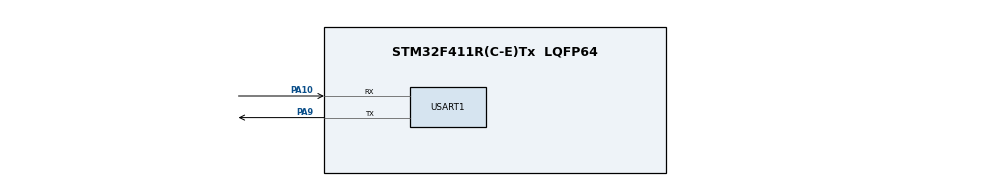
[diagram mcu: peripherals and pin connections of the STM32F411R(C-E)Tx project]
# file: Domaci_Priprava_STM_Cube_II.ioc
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Mcu.Family=STM32F4
Mcu.Name=STM32F411R(C-E)Tx
Mcu.Package=LQFP64
NVIC.PriorityGroup=NVIC_PRIORITYGROUP_4
PA10.Mode=Asynchronous
PA10.Signal=USART1_RX
PA9.Mode=Asynchronous
PA9.Signal=USART1_TX
PH0\ -\ OSC_IN.Mode=HSE-External-Clock-Source
PH0\ -\ OSC_IN.Signal=RCC_OSC_IN
PH1\ -\ OSC_OUT.Mode=HSE-External-Clock-Source
PH1\ -\ OSC_OUT.Signal=RCC_OSC_OUT
ProjectManager.HeapSize=0x200
ProjectManager.StackSize=0x400
ProjectManager.TargetToolchain=TrueSTUDIO
RCC.48MHZClocksFreq_Value=50000000
RCC.AHBFreq_Value=16000000
RCC.APB1CLKDivider=RCC_HCLK_DIV2
RCC.APB1Freq_Value=8000000
RCC.APB1TimFreq_Value=16000000
RCC.APB2Freq_Value=16000000
RCC.APB2TimFreq_Value=16000000
RCC.CortexFreq_Value=16000000
RCC.HCLKFreq_Value=16000000
RCC.HSE_VALUE=8000000
RCC.HSI_VALUE=16000000
RCC.LSE_VALUE=32768
RCC.PLLM=8
RCC.PLLN=100
RCC.SYSCLKFreq_VALUE=16000000
RCC.VCOOutputFreq_Value=200000000
USART1.VirtualMode=VM_ASYNC
board=custom

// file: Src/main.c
/* USER CODE BEGIN Header */
/**
  ******************************************************************************
  * @file           : main.c
  * @brief          : Main program body
  ******************************************************************************
  * @attention
  *
  * <h2><center>&copy; Copyright (c) 2019 STMicroelectronics.
  * All rights reserved.</center></h2>
  *
  * This software component is licensed by ST under BSD 3-Clause license,
  * the "License"; You may not use this file except in compliance with the
  * License. You may obtain a copy of the License at:
  *                        opensource.org/licenses/BSD-3-Clause
  *
  ******************************************************************************
  */
/* USER CODE END Header */

#include "main.h"

UART_HandleTypeDef huart1;

void SystemClock_Config(void);
static void MX_GPIO_Init(void);
static void MX_USART1_UART_Init(void);

int main(void)
{

  /* MCU Configuration--------------------------------------------------------*/

  /* Reset of all peripherals, Initializes the Flash interface and the Systick. */
  HAL_Init();

  /* Configure the system clock */
  SystemClock_Config();

  /* Initialize all configured peripherals */
  MX_GPIO_Init();
  MX_USART1_UART_Init();

  /* Infinite loop */
  while (1)
  {

  }
}

void SystemClock_Config(void)
{
  RCC_OscInitTypeDef RCC_OscInitStruct = {0};
  RCC_ClkInitTypeDef RCC_ClkInitStruct = {0};

  /** Configure the main internal regulator output voltage
  */
  __HAL_RCC_PWR_CLK_ENABLE();
  __HAL_PWR_VOLTAGESCALING_CONFIG(PWR_REGULATOR_VOLTAGE_SCALE1);
  /** Initializes the CPU, AHB and APB busses clocks
  */
  RCC_OscInitStruct.OscillatorType = RCC_OSCILLATORTYPE_HSE;
  RCC_OscInitStruct.HSEState = RCC_HSE_BYPASS;
  RCC_OscInitStruct.PLL.PLLState = RCC_PLL_ON;
  RCC_OscInitStruct.PLL.PLLSource = RCC_PLLSOURCE_HSE;
  RCC_OscInitStruct.PLL.PLLM = 4;
  RCC_OscInitStruct.PLL.PLLN = 100;
  RCC_OscInitStruct.PLL.PLLP = RCC_PLLP_DIV2;
  RCC_OscInitStruct.PLL.PLLQ = 4;
  if (HAL_RCC_OscConfig(&RCC_OscInitStruct) != HAL_OK)
  {
    Error_Handler();
  }
  /** Initializes the CPU, AHB and APB busses clocks
  */
  RCC_ClkInitStruct.ClockType = RCC_CLOCKTYPE_HCLK|RCC_CLOCKTYPE_SYSCLK
                              |RCC_CLOCKTYPE_PCLK1|RCC_CLOCKTYPE_PCLK2;
  RCC_ClkInitStruct.SYSCLKSource = RCC_SYSCLKSOURCE_PLLCLK;
  RCC_ClkInitStruct.AHBCLKDivider = RCC_SYSCLK_DIV1;
  RCC_ClkInitStruct.APB1CLKDivider = RCC_HCLK_DIV2;
  RCC_ClkInitStruct.APB2CLKDivider = RCC_HCLK_DIV1;

  if (HAL_RCC_ClockConfig(&RCC_ClkInitStruct, FLASH_LATENCY_3) != HAL_OK)
  {
    Error_Handler();
  }
}

static void MX_USART1_UART_Init(void)
{

  huart1.Instance = USART1;
  huart1.Init.BaudRate = 115200;
  huart1.Init.WordLength = UART_WORDLENGTH_8B;
  huart1.Init.StopBits = UART_STOPBITS_1;
  huart1.Init.Parity = UART_PARITY_NONE;
  huart1.Init.Mode = UART_MODE_TX_RX;
  huart1.Init.HwFlowCtl = UART_HWCONTROL_NONE;
  huart1.Init.OverSampling = UART_OVERSAMPLING_16;
  if (HAL_UART_Init(&huart1) != HAL_OK)
  {
    Error_Handler();
  }

}

static void MX_GPIO_Init(void)
{

  /* GPIO Ports Clock Enable */
  __HAL_RCC_GPIOH_CLK_ENABLE();
  __HAL_RCC_GPIOA_CLK_ENABLE();

}

void Error_Handler(void)
{
}

/************************ (C) COPYRIGHT STMicroelectronics *****END OF FILE****/
